VERSION 5.7 ;
  NOWIREEXTENSIONATPIN ON ;
  DIVIDERCHAR "/" ;
  BUSBITCHARS "[]" ;
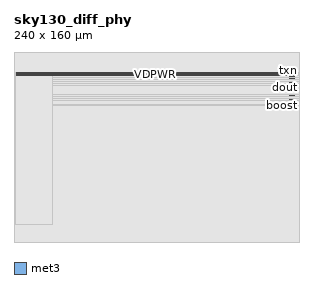
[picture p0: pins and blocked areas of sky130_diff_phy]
MACRO sky130_diff_phy
  CLASS BLOCK ;
  FOREIGN sky130_diff_phy ;
  ORIGIN 0.000 0.000 ;
  SIZE 240.000 BY 160.000 ;
  PIN din
    DIRECTION INPUT ;
    USE SIGNAL ;
    ANTENNAGATEAREA 0.900000 ;
    PORT
      LAYER met3 ;
        RECT 232.000 119.800 236.000 120.200 ;
    END
  END din
  PIN boost
    DIRECTION INPUT ;
    USE SIGNAL ;
    ANTENNAGATEAREA 2.100000 ;
    PORT
      LAYER met3 ;
        RECT 232.000 115.000 236.000 115.400 ;
    END
  END boost
  PIN rxp
    DIRECTION INPUT ;
    USE SIGNAL ;
    ANTENNAGATEAREA 24.000000 ;
    PORT
      LAYER met3 ;
        RECT 232.000 134.200 236.000 134.600 ;
    END
  END rxp
  PIN rxn
    DIRECTION INPUT ;
    USE SIGNAL ;
    ANTENNAGATEAREA 24.000000 ;
    PORT
      LAYER met3 ;
        RECT 232.000 132.600 236.000 133.000 ;
    END
  END rxn
  PIN txp
    DIRECTION OUTPUT ;
    USE SIGNAL ;
    PORT
      LAYER met3 ;
        RECT 232.000 139.000 236.000 139.400 ;
    END
  END txp
  PIN txn
    DIRECTION OUTPUT ;
    USE SIGNAL ;
    PORT
      LAYER met3 ;
        RECT 232.000 137.400 236.000 137.800 ;
    END
  END txn
  PIN dout
    DIRECTION OUTPUT ;
    USE SIGNAL ;
    ANTENNADIFFAREA 1.740000 ;
    PORT
      LAYER met3 ;
        RECT 232.000 123.000 236.000 123.400 ;
    END
  END dout
  PIN VDPWR
    DIRECTION INOUT ;
    USE POWER ;
    PORT
      LAYER met3 ;
        RECT 2.000 140.600 236.000 141.000 ;
    END
  END VDPWR
  PIN VGND
    DIRECTION INOUT ;
    USE GROUND ;
    PORT
      LAYER met3 ;
        RECT 2.000 142.200 236.000 142.600 ;
    END
  END VGND
  OBS
    LAYER met1 ;
      RECT 0.000 0.000 240.000 160.000 ;
    LAYER met2 ;
      RECT 0.000 0.000 240.000 160.000 ;
    LAYER met3 ;
      RECT 0.000 0.000 240.000 114.600 ;
      RECT 0.000 115.800 240.000 119.400 ;
      RECT 0.000 114.600 231.600 115.800 ;
      RECT 236.400 114.600 240.000 115.800 ;
      RECT 0.000 120.600 240.000 122.600 ;
      RECT 0.000 123.800 240.000 132.200 ;
      RECT 0.000 122.600 231.600 123.800 ;
      RECT 236.400 122.600 240.000 123.800 ;
      RECT 0.000 133.400 240.000 133.800 ;
      RECT 0.000 132.200 231.600 133.400 ;
      RECT 236.400 132.200 240.000 133.400 ;
      RECT 0.000 135.000 240.000 137.000 ;
      RECT 0.000 138.200 240.000 138.600 ;
      RECT 0.000 137.000 231.600 138.200 ;
      RECT 236.400 137.000 240.000 138.200 ;
      RECT 0.000 139.800 240.000 140.200 ;
      RECT 0.000 141.400 240.000 141.800 ;
      RECT 0.000 143.000 240.000 160.000 ;
      RECT 0.000 141.800 1.600 143.000 ;
      RECT 236.400 141.800 240.000 143.000 ;
      RECT 0.000 140.200 1.600 141.400 ;
      RECT 236.400 140.200 240.000 141.400 ;
      RECT 0.000 138.600 231.600 139.800 ;
      RECT 236.400 138.600 240.000 139.800 ;
      RECT 0.000 133.800 231.600 135.000 ;
      RECT 236.400 133.800 240.000 135.000 ;
      RECT 0.000 119.400 231.600 120.600 ;
      RECT 236.400 119.400 240.000 120.600 ;
    LAYER met4 ;
      RECT 1.600 14.600 32.800 142.800 ;
  END
END sky130_diff_phy
END LIBRARY

